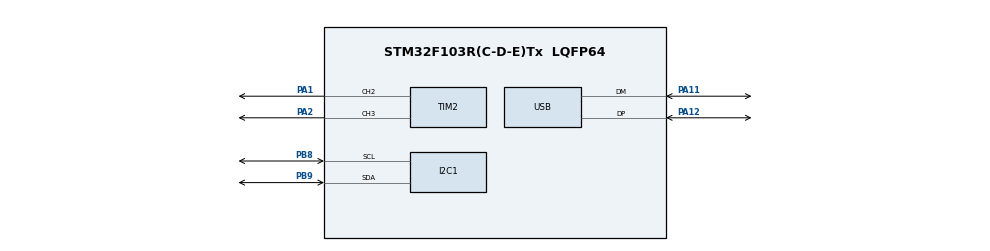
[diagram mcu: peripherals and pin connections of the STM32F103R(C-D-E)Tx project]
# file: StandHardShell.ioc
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I2C1.I2C_Mode=I2C_Fast
Mcu.Family=STM32F1
Mcu.Name=STM32F103R(C-D-E)Tx
Mcu.Package=LQFP64
NVIC.I2C1_ER_IRQn=true\:0\:0\:false\:false\:true\:true\:true
NVIC.I2C1_EV_IRQn=true\:0\:0\:false\:false\:true\:true\:true
NVIC.PriorityGroup=NVIC_PRIORITYGROUP_4
NVIC.TIM2_IRQn=true\:0\:0\:false\:false\:true\:true\:true
NVIC.USB_LP_CAN1_RX0_IRQn=true\:0\:0\:false\:false\:true\:false\:true
PA1.Signal=S_TIM2_CH2
PA11.Mode=Device
PA11.Signal=USB_DM
PA12.Mode=Device
PA12.Signal=USB_DP
PA2.Signal=S_TIM2_CH3
PB8.GPIO_Pu=GPIO_PULLUP
PB8.Mode=I2C
PB8.Signal=I2C1_SCL
PB9.GPIO_Pu=GPIO_PULLUP
PB9.Mode=I2C
PB9.Signal=I2C1_SDA
PD0-OSC_IN.Mode=HSE-External-Oscillator
PD0-OSC_IN.Signal=RCC_OSC_IN
PD1-OSC_OUT.Mode=HSE-External-Oscillator
PD1-OSC_OUT.Signal=RCC_OSC_OUT
ProjectManager.HeapSize=0x200
ProjectManager.StackSize=0x400
ProjectManager.TargetToolchain=STM32CubeIDE
RCC.AHBFreq_Value=48000000
RCC.APB1CLKDivider=RCC_HCLK_DIV2
RCC.APB1Freq_Value=24000000
RCC.APB1TimFreq_Value=48000000
RCC.APB2Freq_Value=48000000
RCC.APB2TimFreq_Value=48000000
RCC.HCLKFreq_Value=48000000
RCC.HSEDivPLL=RCC_HSE_PREDIV_DIV2
RCC.PLLMUL=RCC_PLL_MUL12
RCC.SYSCLKFreq_VALUE=48000000
RCC.SYSCLKSource=RCC_SYSCLKSOURCE_PLLCLK
RCC.USBFreq_Value=48000000
SH.S_TIM2_CH2.0=TIM2_CH2,PWM Generation2 CH2
SH.S_TIM2_CH3.0=TIM2_CH3,PWM Generation3 CH3
TIM2.Channel-PWM\ Generation2\ CH2=TIM_CHANNEL_2
TIM2.Channel-PWM\ Generation3\ CH3=TIM_CHANNEL_3
USB_DEVICE.CLASS_NAME_FS=CDC
USB_DEVICE.VirtualMode=Cdc
USB_DEVICE.VirtualModeFS=Cdc_FS
VP_SYS_VS_ND.Mode=No_Debug
VP_TIM2_VS_ClockSourceINT.Mode=Internal
VP_USB_DEVICE_VS_USB_DEVICE_CDC_FS.Mode=CDC_FS
board=custom

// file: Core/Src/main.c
/* USER CODE BEGIN Header */
/**
  ******************************************************************************
  * @file           : main.c
  * @brief          : Main program body
  ******************************************************************************
  * @attention
  *
  * <h2><center>&copy; Copyright (c) 2021 STMicroelectronics.
  * All rights reserved.</center></h2>
  *
  * This software component is licensed by ST under Ultimate Liberty license
  * SLA0044, the "License"; You may not use this file except in compliance with
  * the License. You may obtain a copy of the License at:
  *                             www.st.com/SLA0044
  *
  ******************************************************************************
  */
/* USER CODE END Header */
#include "main.h"
#include "usb_device.h"
#include "usbd_cdc_if.h"
#include "ADG2128.h"
#include "queue.h"
#include "Control.h"

/* USER CODE BEGIN PTD */
#define  PERIOD_VALUE       (uint32_t)(700 - 1)  /* Period Value  */
#define  PULSE1_VALUE       (uint32_t)(PERIOD_VALUE*0.2)        /* Capture Compare 1 Value  */
#define  PULSE2_VALUE       (uint32_t)(PERIOD_VALUE*0.2) /* Capture Compare 2 Value  */
/* USER CODE END PTD */

I2C_HandleTypeDef hi2c1;

TIM_HandleTypeDef htim2;

/* USER CODE BEGIN PV */
/* Counter Prescaler value */
uint32_t uhPrescalerValue = 0;
/* USER CODE END PV */

void SystemClock_Config(void);
static void MX_GPIO_Init(void);
static void MX_I2C1_Init(void);
static void MX_TIM2_Init(void);

int main(void)
{

  /* MCU Configuration--------------------------------------------------------*/

  /* Reset of all peripherals, Initializes the Flash interface and the Systick. */
  HAL_Init();

  /* Configure the system clock */
  SystemClock_Config();

  /* USER CODE BEGIN SysInit */
  /* Compute the prescaler value to have TIM2 counter clock equal to 2000000 Hz */
  uhPrescalerValue = (uint32_t)(SystemCoreClock / 2000000) - 1;
  /* USER CODE END SysInit */

  /* Initialize all configured peripherals */
  MX_GPIO_Init();
  MX_I2C1_Init();
  MX_TIM2_Init();
  MX_USB_DEVICE_Init();

  /* USER CODE BEGIN 2 */
  init_queue();
  CmdInit();
  /* USER CODE END 2 */

  /* Infinite loop */
  while (1)
  {
	  qextract();

  }
}

void SystemClock_Config(void)
{
  RCC_OscInitTypeDef RCC_OscInitStruct = {0};
  RCC_ClkInitTypeDef RCC_ClkInitStruct = {0};
  RCC_PeriphCLKInitTypeDef PeriphClkInit = {0};

  /** Initializes the RCC Oscillators according to the specified parameters
  * in the RCC_OscInitTypeDef structure.
  */
  RCC_OscInitStruct.OscillatorType = RCC_OSCILLATORTYPE_HSE;
  RCC_OscInitStruct.HSEState = RCC_HSE_ON;
  RCC_OscInitStruct.HSEPredivValue = RCC_HSE_PREDIV_DIV2;
  RCC_OscInitStruct.HSIState = RCC_HSI_ON;
  RCC_OscInitStruct.PLL.PLLState = RCC_PLL_ON;
  RCC_OscInitStruct.PLL.PLLSource = RCC_PLLSOURCE_HSE;
  RCC_OscInitStruct.PLL.PLLMUL = RCC_PLL_MUL8;
  if (HAL_RCC_OscConfig(&RCC_OscInitStruct) != HAL_OK)
  {
    Error_Handler();
  }
  /** Initializes the CPU, AHB and APB buses clocks
  */
  RCC_ClkInitStruct.ClockType = RCC_CLOCKTYPE_HCLK|RCC_CLOCKTYPE_SYSCLK
                              |RCC_CLOCKTYPE_PCLK1|RCC_CLOCKTYPE_PCLK2;
  RCC_ClkInitStruct.SYSCLKSource = RCC_SYSCLKSOURCE_PLLCLK;
  RCC_ClkInitStruct.AHBCLKDivider = RCC_SYSCLK_DIV1;
  RCC_ClkInitStruct.APB1CLKDivider = RCC_HCLK_DIV2;
  RCC_ClkInitStruct.APB2CLKDivider = RCC_HCLK_DIV1;

  if (HAL_RCC_ClockConfig(&RCC_ClkInitStruct, FLASH_LATENCY_1) != HAL_OK)
  {
    Error_Handler();
  }
  PeriphClkInit.PeriphClockSelection = RCC_PERIPHCLK_USB;
  PeriphClkInit.UsbClockSelection = RCC_USBCLKSOURCE_PLL;
  if (HAL_RCCEx_PeriphCLKConfig(&PeriphClkInit) != HAL_OK)
  {
    Error_Handler();
  }
}

static void MX_I2C1_Init(void)
{

  hi2c1.Instance = I2C1;
  hi2c1.Init.ClockSpeed = 400000;
  hi2c1.Init.DutyCycle = I2C_DUTYCYCLE_2;
  hi2c1.Init.OwnAddress1 = 0x3C;//0x70 << 1;
  hi2c1.Init.AddressingMode = I2C_ADDRESSINGMODE_7BIT;
  hi2c1.Init.DualAddressMode = I2C_DUALADDRESS_DISABLE;
  hi2c1.Init.OwnAddress2 = 0xFF;
  hi2c1.Init.GeneralCallMode = I2C_GENERALCALL_DISABLE;
  hi2c1.Init.NoStretchMode = I2C_NOSTRETCH_DISABLE;
  if (HAL_I2C_Init(&hi2c1) != HAL_OK)
  {
    Error_Handler();
  }

}

static void MX_TIM2_Init(void)
{

  TIM_ClockConfigTypeDef sClockSourceConfig = {0};
  TIM_MasterConfigTypeDef sMasterConfig = {0};
  TIM_OC_InitTypeDef sConfigOC = {0};

  htim2.Instance = TIM2;
  htim2.Init.Prescaler = uhPrescalerValue;
  htim2.Init.CounterMode = TIM_COUNTERMODE_UP;
  htim2.Init.Period = PERIOD_VALUE;
  htim2.Init.ClockDivision = TIM_CLOCKDIVISION_DIV1;
  htim2.Init.AutoReloadPreload = TIM_AUTORELOAD_PRELOAD_DISABLE;
  if (HAL_TIM_Base_Init(&htim2) != HAL_OK)
  {
    Error_Handler();
  }
  sClockSourceConfig.ClockSource = TIM_CLOCKSOURCE_INTERNAL;
  if (HAL_TIM_ConfigClockSource(&htim2, &sClockSourceConfig) != HAL_OK)
  {
    Error_Handler();
  }
  if (HAL_TIM_PWM_Init(&htim2) != HAL_OK)
  {
    Error_Handler();
  }
  sMasterConfig.MasterOutputTrigger = TIM_TRGO_RESET;
  sMasterConfig.MasterSlaveMode = TIM_MASTERSLAVEMODE_DISABLE;
  if (HAL_TIMEx_MasterConfigSynchronization(&htim2, &sMasterConfig) != HAL_OK)
  {
    Error_Handler();
  }
  sConfigOC.OCMode = TIM_OCMODE_PWM1;
  sConfigOC.Pulse = PULSE1_VALUE;
  sConfigOC.OCPolarity = TIM_OCPOLARITY_HIGH;
  sConfigOC.OCFastMode = TIM_OCFAST_DISABLE;
  if (HAL_TIM_PWM_ConfigChannel(&htim2, &sConfigOC, TIM_CHANNEL_2) != HAL_OK)
  {
    Error_Handler();
  }
  sConfigOC.Pulse = PULSE2_VALUE;
  if (HAL_TIM_PWM_ConfigChannel(&htim2, &sConfigOC, TIM_CHANNEL_3) != HAL_OK)
  {
    Error_Handler();
  }
  /* USER CODE BEGIN TIM2_Init 2 */
  /* Start channel 2 */
  if (HAL_TIM_PWM_Start(&htim2, TIM_CHANNEL_2) != HAL_OK)
  {
    /* PWM Generation Error */
    Error_Handler();
  }
  /* Start channel 3 */
  if (HAL_TIM_PWM_Start(&htim2, TIM_CHANNEL_3) != HAL_OK)
  {
    /* PWM generation Error */
    Error_Handler();
  }
  /* USER CODE END TIM2_Init 2 */
  HAL_TIM_MspPostInit(&htim2);

}

static void MX_GPIO_Init(void)
{

  /* GPIO Ports Clock Enable */
  __HAL_RCC_GPIOD_CLK_ENABLE();
  __HAL_RCC_GPIOA_CLK_ENABLE();
  __HAL_RCC_GPIOB_CLK_ENABLE();
  __HAL_RCC_GPIOC_CLK_ENABLE();

}

void Error_Handler(void)
{
  __disable_irq();
  while (1)
  {
  }
}

/************************ (C) COPYRIGHT STMicroelectronics *****END OF FILE****/
